VERSION 5.8 ;
BUSBITCHARS "[]" ;
DIVIDERCHAR "/" ;
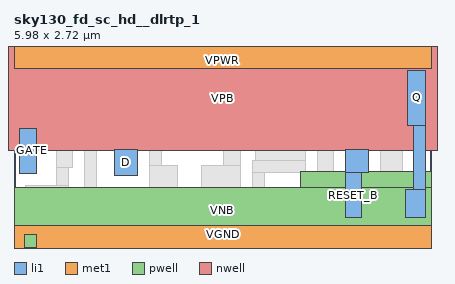
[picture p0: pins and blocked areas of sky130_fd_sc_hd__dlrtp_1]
MACRO sky130_fd_sc_hd__dlrtp_1
  CLASS CORE ;
  FOREIGN sky130_fd_sc_hd__dlrtp_1 ;
  ORIGIN 0.000 0.000 ;
  SIZE 5.980 BY 2.720 ;
  SYMMETRY X Y R90 ;
  SITE unithd ;
  PIN D
    DIRECTION INPUT ;
    USE SIGNAL ;
    ANTENNAGATEAREA 0.159000 ;
    PORT
      LAYER li1 ;
        RECT 1.435 0.955 1.765 1.325 ;
    END
  END D
  PIN GATE
    DIRECTION INPUT ;
    USE CLOCK ;
    ANTENNAGATEAREA 0.159000 ;
    PORT
      LAYER li1 ;
        RECT 0.085 0.985 0.325 1.625 ;
    END
  END GATE
  PIN RESET_B
    DIRECTION INPUT ;
    USE SIGNAL ;
    ANTENNAGATEAREA 0.247500 ;
    PORT
      LAYER li1 ;
        RECT 4.745 0.995 5.075 1.325 ;
        RECT 4.745 0.345 4.975 0.995 ;
    END
  END RESET_B
  PIN VGND
    DIRECTION INOUT ;
    USE GROUND ;
    SHAPE ABUTMENT ;
    PORT
      LAYER met1 ;
        RECT 0.000 -0.240 5.980 0.240 ;
    END
  END VGND
  PIN VNB
    DIRECTION INOUT ;
    USE GROUND ;
    PORT
      LAYER pwell ;
        RECT 4.105 0.785 5.975 1.015 ;
        RECT 0.005 0.105 5.975 0.785 ;
        RECT 0.145 -0.085 0.315 0.105 ;
    END
  END VNB
  PIN VPB
    DIRECTION INOUT ;
    USE POWER ;
    PORT
      LAYER nwell ;
        RECT -0.190 1.305 6.170 2.910 ;
    END
  END VPB
  PIN VPWR
    DIRECTION INOUT ;
    USE POWER ;
    SHAPE ABUTMENT ;
    PORT
      LAYER met1 ;
        RECT 0.000 2.480 5.980 2.960 ;
    END
  END VPWR
  PIN Q
    DIRECTION OUTPUT ;
    USE SIGNAL ;
    ANTENNADIFFAREA 0.429000 ;
    PORT
      LAYER li1 ;
        RECT 5.635 1.670 5.895 2.455 ;
        RECT 5.725 0.745 5.895 1.670 ;
        RECT 5.610 0.345 5.895 0.745 ;
    END
  END Q
  OBS
      LAYER li1 ;
        RECT 0.000 2.635 5.980 2.805 ;
        RECT 0.085 1.965 0.345 2.465 ;
        RECT 0.515 2.135 0.845 2.635 ;
        RECT 0.085 1.795 0.775 1.965 ;
        RECT 0.605 1.400 0.775 1.795 ;
        RECT 1.015 1.685 1.235 2.465 ;
        RECT 0.605 1.070 0.835 1.400 ;
        RECT 0.605 0.805 0.775 1.070 ;
        RECT 0.170 0.635 0.775 0.805 ;
        RECT 0.170 0.345 0.345 0.635 ;
        RECT 0.515 0.085 0.845 0.465 ;
        RECT 1.015 0.345 1.185 1.685 ;
        RECT 1.430 1.665 1.785 2.415 ;
        RECT 1.955 1.835 2.245 2.635 ;
        RECT 2.810 2.255 3.625 2.425 ;
        RECT 2.900 1.785 3.265 1.995 ;
        RECT 1.430 1.495 2.115 1.665 ;
        RECT 1.945 1.095 2.115 1.495 ;
        RECT 2.445 1.625 2.760 1.685 ;
        RECT 3.005 1.635 3.265 1.785 ;
        RECT 2.445 1.355 2.835 1.625 ;
        RECT 3.005 1.095 3.245 1.635 ;
        RECT 3.455 1.325 3.625 2.255 ;
        RECT 3.930 2.135 4.445 2.635 ;
        RECT 4.625 1.865 4.965 2.435 ;
        RECT 5.135 1.915 5.465 2.635 ;
        RECT 3.815 1.735 4.965 1.865 ;
        RECT 3.815 1.535 5.465 1.735 ;
        RECT 4.345 1.505 5.465 1.535 ;
        RECT 3.455 1.165 4.175 1.325 ;
        RECT 1.945 0.785 2.335 1.095 ;
        RECT 1.510 0.765 2.335 0.785 ;
        RECT 2.690 0.765 3.245 1.095 ;
        RECT 3.415 0.995 4.175 1.165 ;
        RECT 1.510 0.615 2.115 0.765 ;
        RECT 1.510 0.345 1.705 0.615 ;
        RECT 3.415 0.535 3.585 0.995 ;
        RECT 4.345 0.805 4.575 1.505 ;
        RECT 5.245 1.325 5.465 1.505 ;
        RECT 5.245 0.995 5.555 1.325 ;
        RECT 1.875 0.085 2.205 0.445 ;
        RECT 2.815 0.365 3.585 0.535 ;
        RECT 3.755 0.085 4.025 0.610 ;
        RECT 4.195 0.295 4.575 0.805 ;
        RECT 5.155 0.085 5.440 0.715 ;
        RECT 0.000 -0.085 5.980 0.085 ;
      LAYER met1 ;
        RECT 1.005 1.940 1.295 1.985 ;
        RECT 2.865 1.940 3.155 1.985 ;
        RECT 1.005 1.800 3.155 1.940 ;
        RECT 1.005 1.755 1.295 1.800 ;
        RECT 2.865 1.755 3.155 1.800 ;
        RECT 0.545 1.600 0.835 1.645 ;
        RECT 2.385 1.600 2.675 1.645 ;
        RECT 0.545 1.460 2.675 1.600 ;
        RECT 0.545 1.415 0.835 1.460 ;
        RECT 2.385 1.415 2.675 1.460 ;
  END
END sky130_fd_sc_hd__dlrtp_1
END LIBRARY
